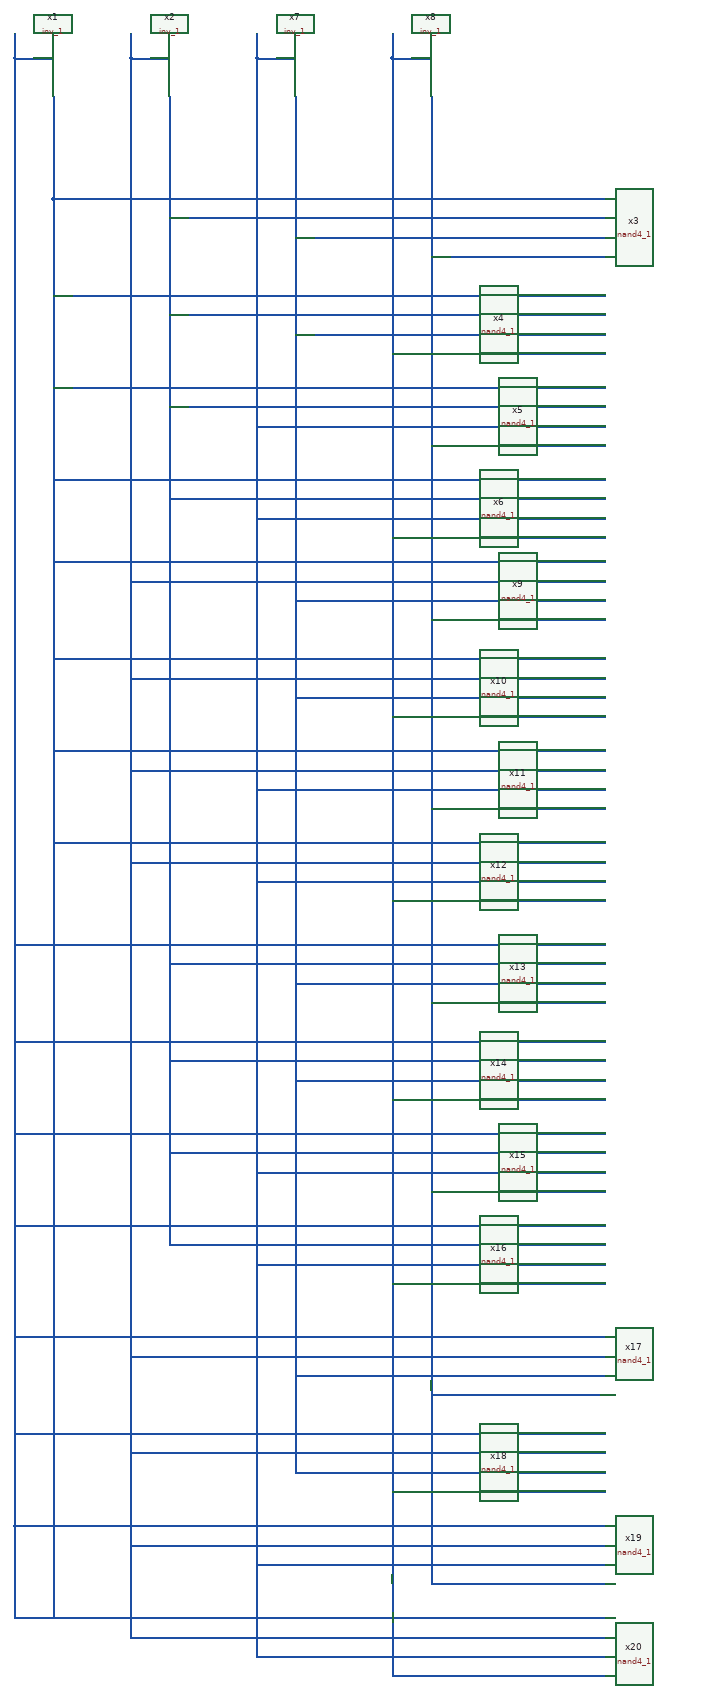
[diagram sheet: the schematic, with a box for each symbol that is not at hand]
v {xschem version=3.1.0 file_version=1.2
}
G {}
K {}
V {}
S {}
E {}
N -830 -260 -750 -260 {
lab=#net1}
N -830 -310 -830 -260 {
lab=#net1}
N -590 -260 -510 -260 {
lab=#net2}
N -590 -310 -590 -260 {
lab=#net2}
N -330 -260 -250 -260 {
lab=#net3}
N -330 -310 -330 -260 {
lab=#net3}
N -50 -260 30 -260 {
lab=#net4}
N -50 -310 -50 -260 {
lab=#net4}
N -750 30 390 30 {}
N -750 -180 -750 30 {}
N 30 -180 30 2500 {}
N -510 70 390 70 {}
N -250 110 390 110 {}
N 30 150 390 150 {}
N -510 270 390 270 {}
N -250 310 390 310 {}
N -50 350 390 350 {}
N -750 230 390 230 {}
N -750 420 390 420 {}
N -750 610 390 610 {}
N -750 780 390 780 {}
N -750 980 390 980 {}
N -750 1170 390 1170 {}
N -750 1360 390 1360 {}
N -830 1570 390 1570 {}
N -830 1770 390 1770 {}
N -830 1960 390 1960 {}
N -830 2150 390 2150 {}
N -830 2380 390 2380 {}
N -830 2580 380 2580 {}
N 380 2580 390 2580 {}
N -830 2690 -830 2770 {}
N -830 2770 -830 2960 {}
N -830 2770 390 2770 {}
N -830 2960 390 2960 {}
N -510 460 390 460 {}
N -510 650 390 650 {}
N -590 820 390 820 {}
N -590 1020 390 1020 {}
N -590 1210 390 1210 {}
N -590 1400 390 1400 {}
N -510 1610 390 1610 {}
N -510 1810 380 1810 {}
N -510 2000 390 2000 {}
N -510 2190 390 2190 {}
N -590 2420 390 2420 {}
N -590 2620 390 2620 {}
N -590 2810 390 2810 {}
N -580 3000 390 3000 {}
N -590 3000 -570 3000 {}
N -330 500 390 500 {}
N -330 690 390 690 {}
N -250 860 390 860 {}
N -250 1060 390 1060 {}
N -330 1250 390 1250 {}
N -330 1440 380 1440 {}
N -250 1650 390 1650 {}
N -250 1850 390 1850 {}
N 380 1810 390 1810 {}
N -330 2040 390 2040 {}
N -330 2230 390 2230 {}
N -250 2460 390 2460 {}
N -250 2660 390 2660 {}
N -330 2850 390 2850 {}
N -330 3040 390 3040 {}
N 30 540 390 540 {}
N -50 730 390 730 {}
N 30 900 390 900 {}
N -50 1100 390 1100 {}
N 30 1290 390 1290 {}
N 380 1440 390 1440 {}
N -50 1480 390 1480 {}
N 30 1690 390 1690 {}
N -50 1890 390 1890 {}
N 30 2080 390 2080 {}
N -50 2270 390 2270 {}
N 30 2500 380 2500 {}
N -50 2700 390 2700 {}
N 30 2890 390 2890 {}
N -50 2890 -50 3080 {}
N -50 3080 390 3080 {}
N -830 -260 -830 2810 {}
N -750 30 -750 2960 {}
N -590 -260 -590 3000 {}
N -510 -180 -510 2190 {}
N -330 -260 -330 3040 {}
N -250 -180 -250 2660 {}
N -50 -260 -50 2950 {}
N 30 2490 30 2890 {}
C {sky130_stdcells/inv_1.sym} -750 -220 1 0 {name=x1 VGND=VGND VNB=VNB VPB=VPB VPWR=VPWR prefix=sky130_fd_sc_hd__ }
C {sky130_stdcells/inv_1.sym} -510 -220 1 0 {name=x2 VGND=VGND VNB=VNB VPB=VPB VPWR=VPWR prefix=sky130_fd_sc_hd__ }
C {sky130_stdcells/inv_1.sym} -250 -220 1 0 {name=x7 VGND=VGND VNB=VNB VPB=VPB VPWR=VPWR prefix=sky130_fd_sc_hd__ }
C {sky130_stdcells/inv_1.sym} 30 -220 1 0 {name=x8 VGND=VGND VNB=VNB VPB=VPB VPWR=VPWR prefix=sky130_fd_sc_hd__ }
C {sky130_stdcells/nand4_1.sym} 450 90 0 0 {name=x3 VGND=VGND VNB=VNB VPB=VPB VPWR=VPWR prefix=sky130_fd_sc_hd__ }
C {sky130_stdcells/nand4_1.sym} 450 290 0 0 {name=x4 VGND=VGND VNB=VNB VPB=VPB VPWR=VPWR prefix=sky130_fd_sc_hd__ }
C {sky130_stdcells/nand4_1.sym} 450 480 0 0 {name=x5 VGND=VGND VNB=VNB VPB=VPB VPWR=VPWR prefix=sky130_fd_sc_hd__ }
C {sky130_stdcells/nand4_1.sym} 450 670 0 0 {name=x6 VGND=VGND VNB=VNB VPB=VPB VPWR=VPWR prefix=sky130_fd_sc_hd__ }
C {sky130_stdcells/nand4_1.sym} 450 840 0 0 {name=x9 VGND=VGND VNB=VNB VPB=VPB VPWR=VPWR prefix=sky130_fd_sc_hd__ }
C {sky130_stdcells/nand4_1.sym} 450 1040 0 0 {name=x10 VGND=VGND VNB=VNB VPB=VPB VPWR=VPWR prefix=sky130_fd_sc_hd__ }
C {sky130_stdcells/nand4_1.sym} 450 1230 0 0 {name=x11 VGND=VGND VNB=VNB VPB=VPB VPWR=VPWR prefix=sky130_fd_sc_hd__ }
C {sky130_stdcells/nand4_1.sym} 450 1420 0 0 {name=x12 VGND=VGND VNB=VNB VPB=VPB VPWR=VPWR prefix=sky130_fd_sc_hd__ }
C {sky130_stdcells/nand4_1.sym} 450 1630 0 0 {name=x13 VGND=VGND VNB=VNB VPB=VPB VPWR=VPWR prefix=sky130_fd_sc_hd__ }
C {sky130_stdcells/nand4_1.sym} 450 1830 0 0 {name=x14 VGND=VGND VNB=VNB VPB=VPB VPWR=VPWR prefix=sky130_fd_sc_hd__ }
C {sky130_stdcells/nand4_1.sym} 450 2020 0 0 {name=x15 VGND=VGND VNB=VNB VPB=VPB VPWR=VPWR prefix=sky130_fd_sc_hd__ }
C {sky130_stdcells/nand4_1.sym} 450 2210 0 0 {name=x16 VGND=VGND VNB=VNB VPB=VPB VPWR=VPWR prefix=sky130_fd_sc_hd__ }
C {sky130_stdcells/nand4_1.sym} 450 2440 0 0 {name=x17 VGND=VGND VNB=VNB VPB=VPB VPWR=VPWR prefix=sky130_fd_sc_hd__ }
C {sky130_stdcells/nand4_1.sym} 450 2640 0 0 {name=x18 VGND=VGND VNB=VNB VPB=VPB VPWR=VPWR prefix=sky130_fd_sc_hd__ }
C {sky130_stdcells/nand4_1.sym} 450 2830 0 0 {name=x19 VGND=VGND VNB=VNB VPB=VPB VPWR=VPWR prefix=sky130_fd_sc_hd__ }
C {sky130_stdcells/nand4_1.sym} 450 3020 0 0 {name=x20 VGND=VGND VNB=VNB VPB=VPB VPWR=VPWR prefix=sky130_fd_sc_hd__ }
